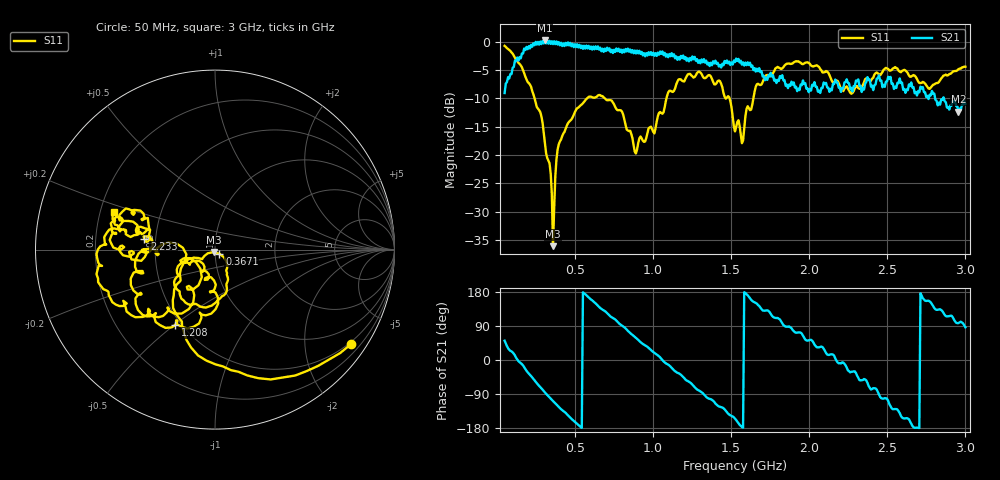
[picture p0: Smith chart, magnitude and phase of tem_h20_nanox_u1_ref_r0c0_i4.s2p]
! nanovna_capture.py 2026-10-26T21:54:02+0900
! NanoVNA-F_V2 fw 0.6.0 SN 4A3639384505514B
! cal: load open short thru cal'ed  over 50000000-3000000000 Hz, 201 points
! points 401, avg 4
! TEM h=20, genuine Nano X, 0 deg, centred, interleaved run G4
# HZ S RI R 50
! S12 and S22 are not measured (written as 0)
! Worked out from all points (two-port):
!   401 points, 50 MHz to 3 GHz, reference 50 ohm
!   highest |S21| = 0.26 dB at 308.1 MHz (marker M1); lowest = -12.4 dB at 2.956 GHz (marker M2)
!   |S21| within 3 dB of the highest: 145.1 MHz to 148 MHz (2.939 MHz wide, 2.01 % of centre); 154.8 MHz to 1.14 GHz (985.1 MHz wide, 152 % of centre) (the widest 2 of 9)
!   lowest |S11| = -36.1 dB at 359.8 MHz (marker M3), VSWR 1.03, Z = 49.2 - j1.35 ohm
!   |S11| at or under -10 dB: 242.1 MHz to 577.5 MHz (335.4 MHz wide, 81.8 % of centre); 692.6 MHz to 1.086 GHz (393.6 MHz wide, 44.3 % of centre); 1.49 GHz to 1.643 GHz (152.5 MHz wide, 9.73 % of centre) (the widest 3 of 4)
!   S12 and S22 are empty: the file has one direction only
!   S11 on the Smith chart (normalised r, x): 50 MHz: 0.44, -3.14; 367.1 MHz: 1.05, -0.05; 1.208 GHz: 0.47, -0.50; 2.233 GHz: 0.43, +0.06; 3 GHz: 0.26, +0.17
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5e7  0.758 -0.5267  0.2223 0.2742  0 0  0 0
1.01625e8  0.3102 -0.7234  0.5541 0.2025  0 0  0 0
1.75375e8  -0.159 -0.5034  0.8274 -0.2824  0 0  0 0
3.08125e8  -0.1189 -0.045  0.0803 -1.027  0 0  0 0
3.5975e8  -0.00747 -0.0137  -0.2985 -0.9078  0 0  0 0
3.67125e8  0.0241 -0.0229  -0.3685 -0.9454  0 0  0 0
4.04e8  0.0626 -0.116  -0.5617 -0.7452  0 0  0 0
5.44125e8  0.0186 -0.2793  -0.9274 -0.0137  0 0  0 0
7.80125e8  -0.2028 -0.145  -0.1182 0.8631  0 0  0 0
8.9075e8  -0.0668 -0.0786  0.4103 0.6752  0 0  0 0
1.03825e9  -0.0147 -0.235  0.7581 0.1338  0 0  0 0
1.207875e9  -0.2205 -0.4186  0.4543 -0.5769  0 0  0 0
1.36275e9  -0.4688 -0.1981  -0.1332 -0.5973  0 0  0 0
1.525e9  -0.1597 -0.026  -0.6008 -0.2821  0 0  0 0
1.56925e9  -0.1078 -0.0675  -0.6283 -0.0368  0 0  0 0
1.694625e9  -0.256 -0.3328  -0.3865 0.3938  0 0  0 0
2.019125e9  -0.609 0.0317  0.263 0.3245  0 0  0 0
2.233e9  -0.3928 0.0591  0.43 -0.1086  0 0  0 0
2.51325e9  -0.5511 0.0935  -0.2102 -0.423  0 0  0 0
2.712375e9  -0.3964 0.1733  -0.4012 0.0277  0 0  0 0
2.95575e9  -0.557 0.1387  -0.0312 0.239  0 0  0 0
3e9  -0.5651 0.2099  0.0178 0.2827  0 0  0 0
